# EOS mock LEF (v1). Synthetic sizes authored for CI;
# see gen_mock.py and mock/README.md.
VERSION 5.8 ;
BUSBITCHARS "[]" ;
DIVIDERCHAR "/" ;
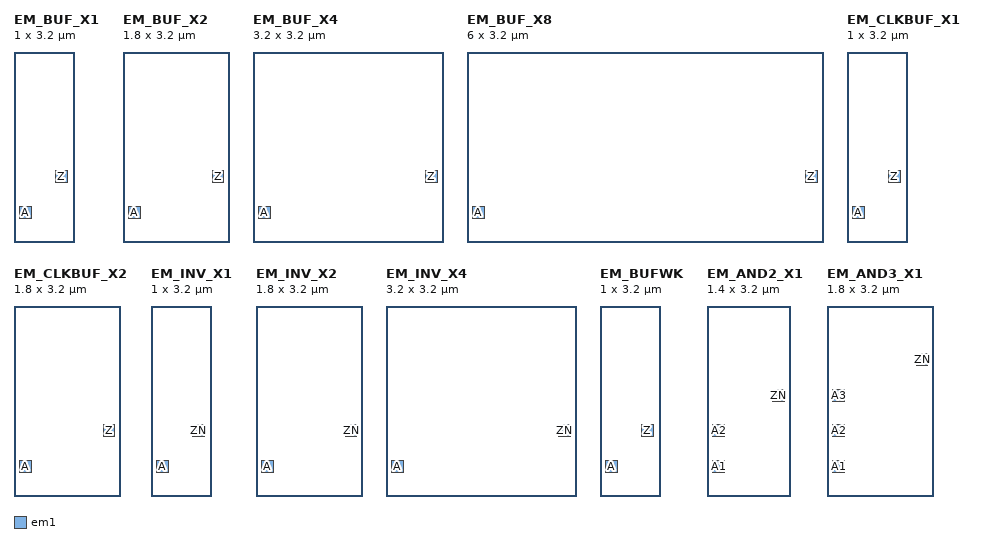
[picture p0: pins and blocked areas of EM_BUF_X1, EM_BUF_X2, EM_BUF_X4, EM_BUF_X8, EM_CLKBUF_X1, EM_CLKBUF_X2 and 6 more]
MACRO EM_BUF_X1
  CLASS CORE ;
  ORIGIN 0 0 ;
  SIZE 1.000000 BY 3.200000 ;
  SYMMETRY X Y ;
  PIN A
    DIRECTION INPUT ;
    USE SIGNAL ;
    PORT
      LAYER em1 ;
        RECT 0.100000 0.400000 0.300000 0.600000 ;
    END
  END A
  PIN Z
    DIRECTION OUTPUT ;
    USE SIGNAL ;
    PORT
      LAYER em1 ;
        RECT 0.700000 1.000000 0.900000 1.200000 ;
    END
  END Z
END EM_BUF_X1
MACRO EM_BUF_X2
  CLASS CORE ;
  ORIGIN 0 0 ;
  SIZE 1.800000 BY 3.200000 ;
  SYMMETRY X Y ;
  PIN A
    DIRECTION INPUT ;
    USE SIGNAL ;
    PORT
      LAYER em1 ;
        RECT 0.100000 0.400000 0.300000 0.600000 ;
    END
  END A
  PIN Z
    DIRECTION OUTPUT ;
    USE SIGNAL ;
    PORT
      LAYER em1 ;
        RECT 1.500000 1.000000 1.700000 1.200000 ;
    END
  END Z
END EM_BUF_X2
MACRO EM_BUF_X4
  CLASS CORE ;
  ORIGIN 0 0 ;
  SIZE 3.200000 BY 3.200000 ;
  SYMMETRY X Y ;
  PIN A
    DIRECTION INPUT ;
    USE SIGNAL ;
    PORT
      LAYER em1 ;
        RECT 0.100000 0.400000 0.300000 0.600000 ;
    END
  END A
  PIN Z
    DIRECTION OUTPUT ;
    USE SIGNAL ;
    PORT
      LAYER em1 ;
        RECT 2.900000 1.000000 3.100000 1.200000 ;
    END
  END Z
END EM_BUF_X4
MACRO EM_BUF_X8
  CLASS CORE ;
  ORIGIN 0 0 ;
  SIZE 6.000000 BY 3.200000 ;
  SYMMETRY X Y ;
  PIN A
    DIRECTION INPUT ;
    USE SIGNAL ;
    PORT
      LAYER em1 ;
        RECT 0.100000 0.400000 0.300000 0.600000 ;
    END
  END A
  PIN Z
    DIRECTION OUTPUT ;
    USE SIGNAL ;
    PORT
      LAYER em1 ;
        RECT 5.700000 1.000000 5.900000 1.200000 ;
    END
  END Z
END EM_BUF_X8
MACRO EM_CLKBUF_X1
  CLASS CORE ;
  ORIGIN 0 0 ;
  SIZE 1.000000 BY 3.200000 ;
  SYMMETRY X Y ;
  PIN A
    DIRECTION INPUT ;
    USE SIGNAL ;
    PORT
      LAYER em1 ;
        RECT 0.100000 0.400000 0.300000 0.600000 ;
    END
  END A
  PIN Z
    DIRECTION OUTPUT ;
    USE SIGNAL ;
    PORT
      LAYER em1 ;
        RECT 0.700000 1.000000 0.900000 1.200000 ;
    END
  END Z
END EM_CLKBUF_X1
MACRO EM_CLKBUF_X2
  CLASS CORE ;
  ORIGIN 0 0 ;
  SIZE 1.800000 BY 3.200000 ;
  SYMMETRY X Y ;
  PIN A
    DIRECTION INPUT ;
    USE SIGNAL ;
    PORT
      LAYER em1 ;
        RECT 0.100000 0.400000 0.300000 0.600000 ;
    END
  END A
  PIN Z
    DIRECTION OUTPUT ;
    USE SIGNAL ;
    PORT
      LAYER em1 ;
        RECT 1.500000 1.000000 1.700000 1.200000 ;
    END
  END Z
END EM_CLKBUF_X2
MACRO EM_INV_X1
  CLASS CORE ;
  ORIGIN 0 0 ;
  SIZE 1.000000 BY 3.200000 ;
  SYMMETRY X Y ;
  PIN A
    DIRECTION INPUT ;
    USE SIGNAL ;
    PORT
      LAYER em1 ;
        RECT 0.100000 0.400000 0.300000 0.600000 ;
    END
  END A
  PIN ZN
    DIRECTION OUTPUT ;
    USE SIGNAL ;
    PORT
      LAYER em1 ;
        RECT 0.700000 1.000000 0.900000 1.200000 ;
    END
  END ZN
END EM_INV_X1
MACRO EM_INV_X2
  CLASS CORE ;
  ORIGIN 0 0 ;
  SIZE 1.800000 BY 3.200000 ;
  SYMMETRY X Y ;
  PIN A
    DIRECTION INPUT ;
    USE SIGNAL ;
    PORT
      LAYER em1 ;
        RECT 0.100000 0.400000 0.300000 0.600000 ;
    END
  END A
  PIN ZN
    DIRECTION OUTPUT ;
    USE SIGNAL ;
    PORT
      LAYER em1 ;
        RECT 1.500000 1.000000 1.700000 1.200000 ;
    END
  END ZN
END EM_INV_X2
MACRO EM_INV_X4
  CLASS CORE ;
  ORIGIN 0 0 ;
  SIZE 3.200000 BY 3.200000 ;
  SYMMETRY X Y ;
  PIN A
    DIRECTION INPUT ;
    USE SIGNAL ;
    PORT
      LAYER em1 ;
        RECT 0.100000 0.400000 0.300000 0.600000 ;
    END
  END A
  PIN ZN
    DIRECTION OUTPUT ;
    USE SIGNAL ;
    PORT
      LAYER em1 ;
        RECT 2.900000 1.000000 3.100000 1.200000 ;
    END
  END ZN
END EM_INV_X4
MACRO EM_BUFWK
  CLASS CORE ;
  ORIGIN 0 0 ;
  SIZE 1.000000 BY 3.200000 ;
  SYMMETRY X Y ;
  PIN A
    DIRECTION INPUT ;
    USE SIGNAL ;
    PORT
      LAYER em1 ;
        RECT 0.100000 0.400000 0.300000 0.600000 ;
    END
  END A
  PIN Z
    DIRECTION OUTPUT ;
    USE SIGNAL ;
    PORT
      LAYER em1 ;
        RECT 0.700000 1.000000 0.900000 1.200000 ;
    END
  END Z
END EM_BUFWK
MACRO EM_AND2_X1
  CLASS CORE ;
  ORIGIN 0 0 ;
  SIZE 1.400000 BY 3.200000 ;
  SYMMETRY X Y ;
  PIN A1
    DIRECTION INPUT ;
    USE SIGNAL ;
    PORT
      LAYER em1 ;
        RECT 0.100000 0.400000 0.300000 0.600000 ;
    END
  END A1
  PIN A2
    DIRECTION INPUT ;
    USE SIGNAL ;
    PORT
      LAYER em1 ;
        RECT 0.100000 1.000000 0.300000 1.200000 ;
    END
  END A2
  PIN ZN
    DIRECTION OUTPUT ;
    USE SIGNAL ;
    PORT
      LAYER em1 ;
        RECT 1.100000 1.600000 1.300000 1.800000 ;
    END
  END ZN
END EM_AND2_X1
MACRO EM_AND3_X1
  CLASS CORE ;
  ORIGIN 0 0 ;
  SIZE 1.800000 BY 3.200000 ;
  SYMMETRY X Y ;
  PIN A1
    DIRECTION INPUT ;
    USE SIGNAL ;
    PORT
      LAYER em1 ;
        RECT 0.100000 0.400000 0.300000 0.600000 ;
    END
  END A1
  PIN A2
    DIRECTION INPUT ;
    USE SIGNAL ;
    PORT
      LAYER em1 ;
        RECT 0.100000 1.000000 0.300000 1.200000 ;
    END
  END A2
  PIN A3
    DIRECTION INPUT ;
    USE SIGNAL ;
    PORT
      LAYER em1 ;
        RECT 0.100000 1.600000 0.300000 1.800000 ;
    END
  END A3
  PIN ZN
    DIRECTION OUTPUT ;
    USE SIGNAL ;
    PORT
      LAYER em1 ;
        RECT 1.500000 2.200000 1.700000 2.400000 ;
    END
  END ZN
END EM_AND3_X1
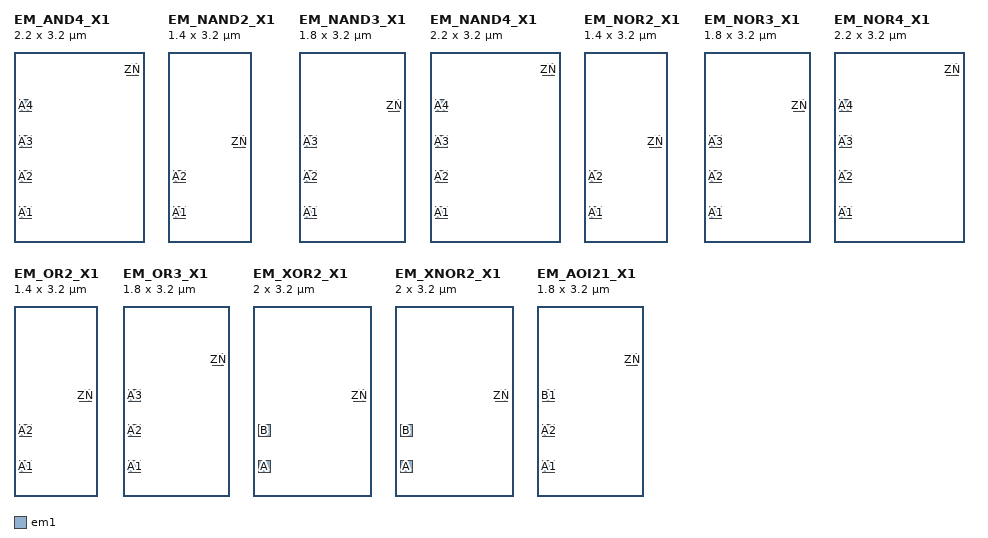
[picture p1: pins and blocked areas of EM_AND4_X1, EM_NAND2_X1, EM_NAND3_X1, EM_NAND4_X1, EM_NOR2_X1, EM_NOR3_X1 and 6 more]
MACRO EM_AND4_X1
  CLASS CORE ;
  ORIGIN 0 0 ;
  SIZE 2.200000 BY 3.200000 ;
  SYMMETRY X Y ;
  PIN A1
    DIRECTION INPUT ;
    USE SIGNAL ;
    PORT
      LAYER em1 ;
        RECT 0.100000 0.400000 0.300000 0.600000 ;
    END
  END A1
  PIN A2
    DIRECTION INPUT ;
    USE SIGNAL ;
    PORT
      LAYER em1 ;
        RECT 0.100000 1.000000 0.300000 1.200000 ;
    END
  END A2
  PIN A3
    DIRECTION INPUT ;
    USE SIGNAL ;
    PORT
      LAYER em1 ;
        RECT 0.100000 1.600000 0.300000 1.800000 ;
    END
  END A3
  PIN A4
    DIRECTION INPUT ;
    USE SIGNAL ;
    PORT
      LAYER em1 ;
        RECT 0.100000 2.200000 0.300000 2.400000 ;
    END
  END A4
  PIN ZN
    DIRECTION OUTPUT ;
    USE SIGNAL ;
    PORT
      LAYER em1 ;
        RECT 1.900000 2.800000 2.100000 3.000000 ;
    END
  END ZN
END EM_AND4_X1
MACRO EM_NAND2_X1
  CLASS CORE ;
  ORIGIN 0 0 ;
  SIZE 1.400000 BY 3.200000 ;
  SYMMETRY X Y ;
  PIN A1
    DIRECTION INPUT ;
    USE SIGNAL ;
    PORT
      LAYER em1 ;
        RECT 0.100000 0.400000 0.300000 0.600000 ;
    END
  END A1
  PIN A2
    DIRECTION INPUT ;
    USE SIGNAL ;
    PORT
      LAYER em1 ;
        RECT 0.100000 1.000000 0.300000 1.200000 ;
    END
  END A2
  PIN ZN
    DIRECTION OUTPUT ;
    USE SIGNAL ;
    PORT
      LAYER em1 ;
        RECT 1.100000 1.600000 1.300000 1.800000 ;
    END
  END ZN
END EM_NAND2_X1
MACRO EM_NAND3_X1
  CLASS CORE ;
  ORIGIN 0 0 ;
  SIZE 1.800000 BY 3.200000 ;
  SYMMETRY X Y ;
  PIN A1
    DIRECTION INPUT ;
    USE SIGNAL ;
    PORT
      LAYER em1 ;
        RECT 0.100000 0.400000 0.300000 0.600000 ;
    END
  END A1
  PIN A2
    DIRECTION INPUT ;
    USE SIGNAL ;
    PORT
      LAYER em1 ;
        RECT 0.100000 1.000000 0.300000 1.200000 ;
    END
  END A2
  PIN A3
    DIRECTION INPUT ;
    USE SIGNAL ;
    PORT
      LAYER em1 ;
        RECT 0.100000 1.600000 0.300000 1.800000 ;
    END
  END A3
  PIN ZN
    DIRECTION OUTPUT ;
    USE SIGNAL ;
    PORT
      LAYER em1 ;
        RECT 1.500000 2.200000 1.700000 2.400000 ;
    END
  END ZN
END EM_NAND3_X1
MACRO EM_NAND4_X1
  CLASS CORE ;
  ORIGIN 0 0 ;
  SIZE 2.200000 BY 3.200000 ;
  SYMMETRY X Y ;
  PIN A1
    DIRECTION INPUT ;
    USE SIGNAL ;
    PORT
      LAYER em1 ;
        RECT 0.100000 0.400000 0.300000 0.600000 ;
    END
  END A1
  PIN A2
    DIRECTION INPUT ;
    USE SIGNAL ;
    PORT
      LAYER em1 ;
        RECT 0.100000 1.000000 0.300000 1.200000 ;
    END
  END A2
  PIN A3
    DIRECTION INPUT ;
    USE SIGNAL ;
    PORT
      LAYER em1 ;
        RECT 0.100000 1.600000 0.300000 1.800000 ;
    END
  END A3
  PIN A4
    DIRECTION INPUT ;
    USE SIGNAL ;
    PORT
      LAYER em1 ;
        RECT 0.100000 2.200000 0.300000 2.400000 ;
    END
  END A4
  PIN ZN
    DIRECTION OUTPUT ;
    USE SIGNAL ;
    PORT
      LAYER em1 ;
        RECT 1.900000 2.800000 2.100000 3.000000 ;
    END
  END ZN
END EM_NAND4_X1
MACRO EM_NOR2_X1
  CLASS CORE ;
  ORIGIN 0 0 ;
  SIZE 1.400000 BY 3.200000 ;
  SYMMETRY X Y ;
  PIN A1
    DIRECTION INPUT ;
    USE SIGNAL ;
    PORT
      LAYER em1 ;
        RECT 0.100000 0.400000 0.300000 0.600000 ;
    END
  END A1
  PIN A2
    DIRECTION INPUT ;
    USE SIGNAL ;
    PORT
      LAYER em1 ;
        RECT 0.100000 1.000000 0.300000 1.200000 ;
    END
  END A2
  PIN ZN
    DIRECTION OUTPUT ;
    USE SIGNAL ;
    PORT
      LAYER em1 ;
        RECT 1.100000 1.600000 1.300000 1.800000 ;
    END
  END ZN
END EM_NOR2_X1
MACRO EM_NOR3_X1
  CLASS CORE ;
  ORIGIN 0 0 ;
  SIZE 1.800000 BY 3.200000 ;
  SYMMETRY X Y ;
  PIN A1
    DIRECTION INPUT ;
    USE SIGNAL ;
    PORT
      LAYER em1 ;
        RECT 0.100000 0.400000 0.300000 0.600000 ;
    END
  END A1
  PIN A2
    DIRECTION INPUT ;
    USE SIGNAL ;
    PORT
      LAYER em1 ;
        RECT 0.100000 1.000000 0.300000 1.200000 ;
    END
  END A2
  PIN A3
    DIRECTION INPUT ;
    USE SIGNAL ;
    PORT
      LAYER em1 ;
        RECT 0.100000 1.600000 0.300000 1.800000 ;
    END
  END A3
  PIN ZN
    DIRECTION OUTPUT ;
    USE SIGNAL ;
    PORT
      LAYER em1 ;
        RECT 1.500000 2.200000 1.700000 2.400000 ;
    END
  END ZN
END EM_NOR3_X1
MACRO EM_NOR4_X1
  CLASS CORE ;
  ORIGIN 0 0 ;
  SIZE 2.200000 BY 3.200000 ;
  SYMMETRY X Y ;
  PIN A1
    DIRECTION INPUT ;
    USE SIGNAL ;
    PORT
      LAYER em1 ;
        RECT 0.100000 0.400000 0.300000 0.600000 ;
    END
  END A1
  PIN A2
    DIRECTION INPUT ;
    USE SIGNAL ;
    PORT
      LAYER em1 ;
        RECT 0.100000 1.000000 0.300000 1.200000 ;
    END
  END A2
  PIN A3
    DIRECTION INPUT ;
    USE SIGNAL ;
    PORT
      LAYER em1 ;
        RECT 0.100000 1.600000 0.300000 1.800000 ;
    END
  END A3
  PIN A4
    DIRECTION INPUT ;
    USE SIGNAL ;
    PORT
      LAYER em1 ;
        RECT 0.100000 2.200000 0.300000 2.400000 ;
    END
  END A4
  PIN ZN
    DIRECTION OUTPUT ;
    USE SIGNAL ;
    PORT
      LAYER em1 ;
        RECT 1.900000 2.800000 2.100000 3.000000 ;
    END
  END ZN
END EM_NOR4_X1
MACRO EM_OR2_X1
  CLASS CORE ;
  ORIGIN 0 0 ;
  SIZE 1.400000 BY 3.200000 ;
  SYMMETRY X Y ;
  PIN A1
    DIRECTION INPUT ;
    USE SIGNAL ;
    PORT
      LAYER em1 ;
        RECT 0.100000 0.400000 0.300000 0.600000 ;
    END
  END A1
  PIN A2
    DIRECTION INPUT ;
    USE SIGNAL ;
    PORT
      LAYER em1 ;
        RECT 0.100000 1.000000 0.300000 1.200000 ;
    END
  END A2
  PIN ZN
    DIRECTION OUTPUT ;
    USE SIGNAL ;
    PORT
      LAYER em1 ;
        RECT 1.100000 1.600000 1.300000 1.800000 ;
    END
  END ZN
END EM_OR2_X1
MACRO EM_OR3_X1
  CLASS CORE ;
  ORIGIN 0 0 ;
  SIZE 1.800000 BY 3.200000 ;
  SYMMETRY X Y ;
  PIN A1
    DIRECTION INPUT ;
    USE SIGNAL ;
    PORT
      LAYER em1 ;
        RECT 0.100000 0.400000 0.300000 0.600000 ;
    END
  END A1
  PIN A2
    DIRECTION INPUT ;
    USE SIGNAL ;
    PORT
      LAYER em1 ;
        RECT 0.100000 1.000000 0.300000 1.200000 ;
    END
  END A2
  PIN A3
    DIRECTION INPUT ;
    USE SIGNAL ;
    PORT
      LAYER em1 ;
        RECT 0.100000 1.600000 0.300000 1.800000 ;
    END
  END A3
  PIN ZN
    DIRECTION OUTPUT ;
    USE SIGNAL ;
    PORT
      LAYER em1 ;
        RECT 1.500000 2.200000 1.700000 2.400000 ;
    END
  END ZN
END EM_OR3_X1
MACRO EM_XOR2_X1
  CLASS CORE ;
  ORIGIN 0 0 ;
  SIZE 2.000000 BY 3.200000 ;
  SYMMETRY X Y ;
  PIN A
    DIRECTION INPUT ;
    USE SIGNAL ;
    PORT
      LAYER em1 ;
        RECT 0.100000 0.400000 0.300000 0.600000 ;
    END
  END A
  PIN B
    DIRECTION INPUT ;
    USE SIGNAL ;
    PORT
      LAYER em1 ;
        RECT 0.100000 1.000000 0.300000 1.200000 ;
    END
  END B
  PIN ZN
    DIRECTION OUTPUT ;
    USE SIGNAL ;
    PORT
      LAYER em1 ;
        RECT 1.700000 1.600000 1.900000 1.800000 ;
    END
  END ZN
END EM_XOR2_X1
MACRO EM_XNOR2_X1
  CLASS CORE ;
  ORIGIN 0 0 ;
  SIZE 2.000000 BY 3.200000 ;
  SYMMETRY X Y ;
  PIN A
    DIRECTION INPUT ;
    USE SIGNAL ;
    PORT
      LAYER em1 ;
        RECT 0.100000 0.400000 0.300000 0.600000 ;
    END
  END A
  PIN B
    DIRECTION INPUT ;
    USE SIGNAL ;
    PORT
      LAYER em1 ;
        RECT 0.100000 1.000000 0.300000 1.200000 ;
    END
  END B
  PIN ZN
    DIRECTION OUTPUT ;
    USE SIGNAL ;
    PORT
      LAYER em1 ;
        RECT 1.700000 1.600000 1.900000 1.800000 ;
    END
  END ZN
END EM_XNOR2_X1
MACRO EM_AOI21_X1
  CLASS CORE ;
  ORIGIN 0 0 ;
  SIZE 1.800000 BY 3.200000 ;
  SYMMETRY X Y ;
  PIN A1
    DIRECTION INPUT ;
    USE SIGNAL ;
    PORT
      LAYER em1 ;
        RECT 0.100000 0.400000 0.300000 0.600000 ;
    END
  END A1
  PIN A2
    DIRECTION INPUT ;
    USE SIGNAL ;
    PORT
      LAYER em1 ;
        RECT 0.100000 1.000000 0.300000 1.200000 ;
    END
  END A2
  PIN B1
    DIRECTION INPUT ;
    USE SIGNAL ;
    PORT
      LAYER em1 ;
        RECT 0.100000 1.600000 0.300000 1.800000 ;
    END
  END B1
  PIN ZN
    DIRECTION OUTPUT ;
    USE SIGNAL ;
    PORT
      LAYER em1 ;
        RECT 1.500000 2.200000 1.700000 2.400000 ;
    END
  END ZN
END EM_AOI21_X1
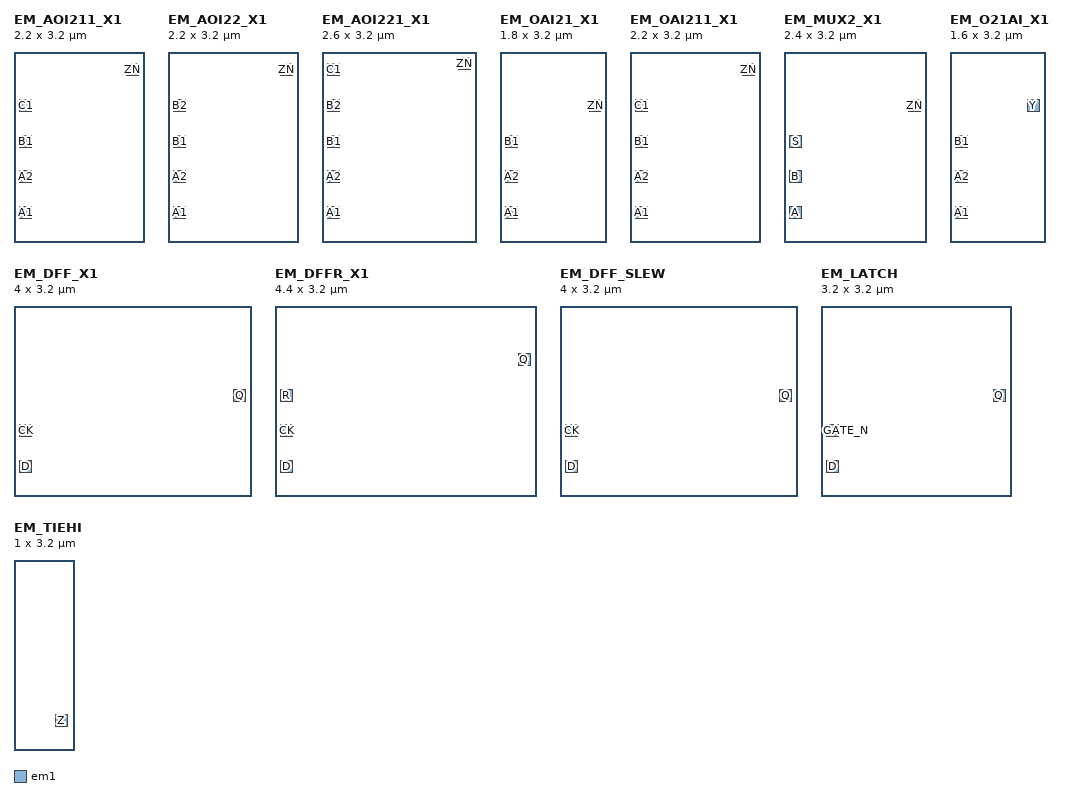
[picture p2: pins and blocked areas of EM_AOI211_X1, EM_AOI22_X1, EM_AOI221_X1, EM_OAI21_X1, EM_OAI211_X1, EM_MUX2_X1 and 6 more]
MACRO EM_AOI211_X1
  CLASS CORE ;
  ORIGIN 0 0 ;
  SIZE 2.200000 BY 3.200000 ;
  SYMMETRY X Y ;
  PIN A1
    DIRECTION INPUT ;
    USE SIGNAL ;
    PORT
      LAYER em1 ;
        RECT 0.100000 0.400000 0.300000 0.600000 ;
    END
  END A1
  PIN A2
    DIRECTION INPUT ;
    USE SIGNAL ;
    PORT
      LAYER em1 ;
        RECT 0.100000 1.000000 0.300000 1.200000 ;
    END
  END A2
  PIN B1
    DIRECTION INPUT ;
    USE SIGNAL ;
    PORT
      LAYER em1 ;
        RECT 0.100000 1.600000 0.300000 1.800000 ;
    END
  END B1
  PIN C1
    DIRECTION INPUT ;
    USE SIGNAL ;
    PORT
      LAYER em1 ;
        RECT 0.100000 2.200000 0.300000 2.400000 ;
    END
  END C1
  PIN ZN
    DIRECTION OUTPUT ;
    USE SIGNAL ;
    PORT
      LAYER em1 ;
        RECT 1.900000 2.800000 2.100000 3.000000 ;
    END
  END ZN
END EM_AOI211_X1
MACRO EM_AOI22_X1
  CLASS CORE ;
  ORIGIN 0 0 ;
  SIZE 2.200000 BY 3.200000 ;
  SYMMETRY X Y ;
  PIN A1
    DIRECTION INPUT ;
    USE SIGNAL ;
    PORT
      LAYER em1 ;
        RECT 0.100000 0.400000 0.300000 0.600000 ;
    END
  END A1
  PIN A2
    DIRECTION INPUT ;
    USE SIGNAL ;
    PORT
      LAYER em1 ;
        RECT 0.100000 1.000000 0.300000 1.200000 ;
    END
  END A2
  PIN B1
    DIRECTION INPUT ;
    USE SIGNAL ;
    PORT
      LAYER em1 ;
        RECT 0.100000 1.600000 0.300000 1.800000 ;
    END
  END B1
  PIN B2
    DIRECTION INPUT ;
    USE SIGNAL ;
    PORT
      LAYER em1 ;
        RECT 0.100000 2.200000 0.300000 2.400000 ;
    END
  END B2
  PIN ZN
    DIRECTION OUTPUT ;
    USE SIGNAL ;
    PORT
      LAYER em1 ;
        RECT 1.900000 2.800000 2.100000 3.000000 ;
    END
  END ZN
END EM_AOI22_X1
MACRO EM_AOI221_X1
  CLASS CORE ;
  ORIGIN 0 0 ;
  SIZE 2.600000 BY 3.200000 ;
  SYMMETRY X Y ;
  PIN A1
    DIRECTION INPUT ;
    USE SIGNAL ;
    PORT
      LAYER em1 ;
        RECT 0.100000 0.400000 0.300000 0.600000 ;
    END
  END A1
  PIN A2
    DIRECTION INPUT ;
    USE SIGNAL ;
    PORT
      LAYER em1 ;
        RECT 0.100000 1.000000 0.300000 1.200000 ;
    END
  END A2
  PIN B1
    DIRECTION INPUT ;
    USE SIGNAL ;
    PORT
      LAYER em1 ;
        RECT 0.100000 1.600000 0.300000 1.800000 ;
    END
  END B1
  PIN B2
    DIRECTION INPUT ;
    USE SIGNAL ;
    PORT
      LAYER em1 ;
        RECT 0.100000 2.200000 0.300000 2.400000 ;
    END
  END B2
  PIN C1
    DIRECTION INPUT ;
    USE SIGNAL ;
    PORT
      LAYER em1 ;
        RECT 0.100000 2.800000 0.300000 3.000000 ;
    END
  END C1
  PIN ZN
    DIRECTION OUTPUT ;
    USE SIGNAL ;
    PORT
      LAYER em1 ;
        RECT 2.300000 2.900000 2.500000 3.100000 ;
    END
  END ZN
END EM_AOI221_X1
MACRO EM_OAI21_X1
  CLASS CORE ;
  ORIGIN 0 0 ;
  SIZE 1.800000 BY 3.200000 ;
  SYMMETRY X Y ;
  PIN A1
    DIRECTION INPUT ;
    USE SIGNAL ;
    PORT
      LAYER em1 ;
        RECT 0.100000 0.400000 0.300000 0.600000 ;
    END
  END A1
  PIN A2
    DIRECTION INPUT ;
    USE SIGNAL ;
    PORT
      LAYER em1 ;
        RECT 0.100000 1.000000 0.300000 1.200000 ;
    END
  END A2
  PIN B1
    DIRECTION INPUT ;
    USE SIGNAL ;
    PORT
      LAYER em1 ;
        RECT 0.100000 1.600000 0.300000 1.800000 ;
    END
  END B1
  PIN ZN
    DIRECTION OUTPUT ;
    USE SIGNAL ;
    PORT
      LAYER em1 ;
        RECT 1.500000 2.200000 1.700000 2.400000 ;
    END
  END ZN
END EM_OAI21_X1
MACRO EM_OAI211_X1
  CLASS CORE ;
  ORIGIN 0 0 ;
  SIZE 2.200000 BY 3.200000 ;
  SYMMETRY X Y ;
  PIN A1
    DIRECTION INPUT ;
    USE SIGNAL ;
    PORT
      LAYER em1 ;
        RECT 0.100000 0.400000 0.300000 0.600000 ;
    END
  END A1
  PIN A2
    DIRECTION INPUT ;
    USE SIGNAL ;
    PORT
      LAYER em1 ;
        RECT 0.100000 1.000000 0.300000 1.200000 ;
    END
  END A2
  PIN B1
    DIRECTION INPUT ;
    USE SIGNAL ;
    PORT
      LAYER em1 ;
        RECT 0.100000 1.600000 0.300000 1.800000 ;
    END
  END B1
  PIN C1
    DIRECTION INPUT ;
    USE SIGNAL ;
    PORT
      LAYER em1 ;
        RECT 0.100000 2.200000 0.300000 2.400000 ;
    END
  END C1
  PIN ZN
    DIRECTION OUTPUT ;
    USE SIGNAL ;
    PORT
      LAYER em1 ;
        RECT 1.900000 2.800000 2.100000 3.000000 ;
    END
  END ZN
END EM_OAI211_X1
MACRO EM_MUX2_X1
  CLASS CORE ;
  ORIGIN 0 0 ;
  SIZE 2.400000 BY 3.200000 ;
  SYMMETRY X Y ;
  PIN A
    DIRECTION INPUT ;
    USE SIGNAL ;
    PORT
      LAYER em1 ;
        RECT 0.100000 0.400000 0.300000 0.600000 ;
    END
  END A
  PIN B
    DIRECTION INPUT ;
    USE SIGNAL ;
    PORT
      LAYER em1 ;
        RECT 0.100000 1.000000 0.300000 1.200000 ;
    END
  END B
  PIN S
    DIRECTION INPUT ;
    USE SIGNAL ;
    PORT
      LAYER em1 ;
        RECT 0.100000 1.600000 0.300000 1.800000 ;
    END
  END S
  PIN ZN
    DIRECTION OUTPUT ;
    USE SIGNAL ;
    PORT
      LAYER em1 ;
        RECT 2.100000 2.200000 2.300000 2.400000 ;
    END
  END ZN
END EM_MUX2_X1
MACRO EM_O21AI_X1
  CLASS CORE ;
  ORIGIN 0 0 ;
  SIZE 1.600000 BY 3.200000 ;
  SYMMETRY X Y ;
  PIN A1
    DIRECTION INPUT ;
    USE SIGNAL ;
    PORT
      LAYER em1 ;
        RECT 0.100000 0.400000 0.300000 0.600000 ;
    END
  END A1
  PIN A2
    DIRECTION INPUT ;
    USE SIGNAL ;
    PORT
      LAYER em1 ;
        RECT 0.100000 1.000000 0.300000 1.200000 ;
    END
  END A2
  PIN B1
    DIRECTION INPUT ;
    USE SIGNAL ;
    PORT
      LAYER em1 ;
        RECT 0.100000 1.600000 0.300000 1.800000 ;
    END
  END B1
  PIN Y
    DIRECTION OUTPUT ;
    USE SIGNAL ;
    PORT
      LAYER em1 ;
        RECT 1.300000 2.200000 1.500000 2.400000 ;
    END
  END Y
END EM_O21AI_X1
MACRO EM_DFF_X1
  CLASS CORE ;
  ORIGIN 0 0 ;
  SIZE 4.000000 BY 3.200000 ;
  SYMMETRY X Y ;
  PIN D
    DIRECTION INPUT ;
    USE SIGNAL ;
    PORT
      LAYER em1 ;
        RECT 0.100000 0.400000 0.300000 0.600000 ;
    END
  END D
  PIN CK
    DIRECTION INPUT ;
    USE CLOCK ;
    PORT
      LAYER em1 ;
        RECT 0.100000 1.000000 0.300000 1.200000 ;
    END
  END CK
  PIN Q
    DIRECTION OUTPUT ;
    USE SIGNAL ;
    PORT
      LAYER em1 ;
        RECT 3.700000 1.600000 3.900000 1.800000 ;
    END
  END Q
END EM_DFF_X1
MACRO EM_DFFR_X1
  CLASS CORE ;
  ORIGIN 0 0 ;
  SIZE 4.400000 BY 3.200000 ;
  SYMMETRY X Y ;
  PIN D
    DIRECTION INPUT ;
    USE SIGNAL ;
    PORT
      LAYER em1 ;
        RECT 0.100000 0.400000 0.300000 0.600000 ;
    END
  END D
  PIN CK
    DIRECTION INPUT ;
    USE CLOCK ;
    PORT
      LAYER em1 ;
        RECT 0.100000 1.000000 0.300000 1.200000 ;
    END
  END CK
  PIN R
    DIRECTION INPUT ;
    USE SIGNAL ;
    PORT
      LAYER em1 ;
        RECT 0.100000 1.600000 0.300000 1.800000 ;
    END
  END R
  PIN Q
    DIRECTION OUTPUT ;
    USE SIGNAL ;
    PORT
      LAYER em1 ;
        RECT 4.100000 2.200000 4.300000 2.400000 ;
    END
  END Q
END EM_DFFR_X1
MACRO EM_DFF_SLEW
  CLASS CORE ;
  ORIGIN 0 0 ;
  SIZE 4.000000 BY 3.200000 ;
  SYMMETRY X Y ;
  PIN D
    DIRECTION INPUT ;
    USE SIGNAL ;
    PORT
      LAYER em1 ;
        RECT 0.100000 0.400000 0.300000 0.600000 ;
    END
  END D
  PIN CK
    DIRECTION INPUT ;
    USE CLOCK ;
    PORT
      LAYER em1 ;
        RECT 0.100000 1.000000 0.300000 1.200000 ;
    END
  END CK
  PIN Q
    DIRECTION OUTPUT ;
    USE SIGNAL ;
    PORT
      LAYER em1 ;
        RECT 3.700000 1.600000 3.900000 1.800000 ;
    END
  END Q
END EM_DFF_SLEW
MACRO EM_LATCH
  CLASS CORE ;
  ORIGIN 0 0 ;
  SIZE 3.200000 BY 3.200000 ;
  SYMMETRY X Y ;
  PIN D
    DIRECTION INPUT ;
    USE SIGNAL ;
    PORT
      LAYER em1 ;
        RECT 0.100000 0.400000 0.300000 0.600000 ;
    END
  END D
  PIN GATE_N
    DIRECTION INPUT ;
    USE CLOCK ;
    PORT
      LAYER em1 ;
        RECT 0.100000 1.000000 0.300000 1.200000 ;
    END
  END GATE_N
  PIN Q
    DIRECTION OUTPUT ;
    USE SIGNAL ;
    PORT
      LAYER em1 ;
        RECT 2.900000 1.600000 3.100000 1.800000 ;
    END
  END Q
END EM_LATCH
MACRO EM_TIEHI
  CLASS CORE ;
  ORIGIN 0 0 ;
  SIZE 1.000000 BY 3.200000 ;
  SYMMETRY X Y ;
  PIN Z
    DIRECTION OUTPUT ;
    USE SIGNAL ;
    PORT
      LAYER em1 ;
        RECT 0.700000 0.400000 0.900000 0.600000 ;
    END
  END Z
END EM_TIEHI
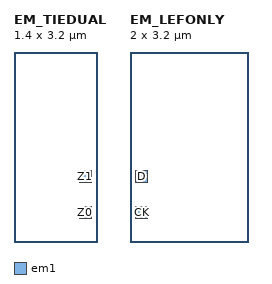
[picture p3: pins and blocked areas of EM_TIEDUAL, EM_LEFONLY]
MACRO EM_TIEDUAL
  CLASS CORE ;
  ORIGIN 0 0 ;
  SIZE 1.400000 BY 3.200000 ;
  SYMMETRY X Y ;
  PIN Z0
    DIRECTION OUTPUT ;
    USE SIGNAL ;
    PORT
      LAYER em1 ;
        RECT 1.100000 0.400000 1.300000 0.600000 ;
    END
  END Z0
  PIN Z1
    DIRECTION OUTPUT ;
    USE SIGNAL ;
    PORT
      LAYER em1 ;
        RECT 1.100000 1.000000 1.300000 1.200000 ;
    END
  END Z1
END EM_TIEDUAL
MACRO EM_FILL
  CLASS CORE ;
  ORIGIN 0 0 ;
  SIZE 1.000000 BY 3.200000 ;
  SYMMETRY X Y ;
END EM_FILL
MACRO EM_TAP
  CLASS CORE ;
  ORIGIN 0 0 ;
  SIZE 1.000000 BY 3.200000 ;
  SYMMETRY X Y ;
END EM_TAP
MACRO EM_LEFONLY
  CLASS CORE ;
  ORIGIN 0 0 ;
  SIZE 2.000000 BY 3.200000 ;
  SYMMETRY X Y ;
  PIN CK
    DIRECTION INPUT ;
    USE SIGNAL ;
    PORT
      LAYER em1 ;
        RECT 0.100000 0.400000 0.300000 0.600000 ;
    END
  END CK
  PIN D
    DIRECTION INPUT ;
    USE SIGNAL ;
    PORT
      LAYER em1 ;
        RECT 0.100000 1.000000 0.300000 1.200000 ;
    END
  END D
END EM_LEFONLY
END LIBRARY
